VERSION 5.7 ;
  NOWIREEXTENSIONATPIN ON ;
  DIVIDERCHAR "/" ;
  BUSBITCHARS "[]" ;
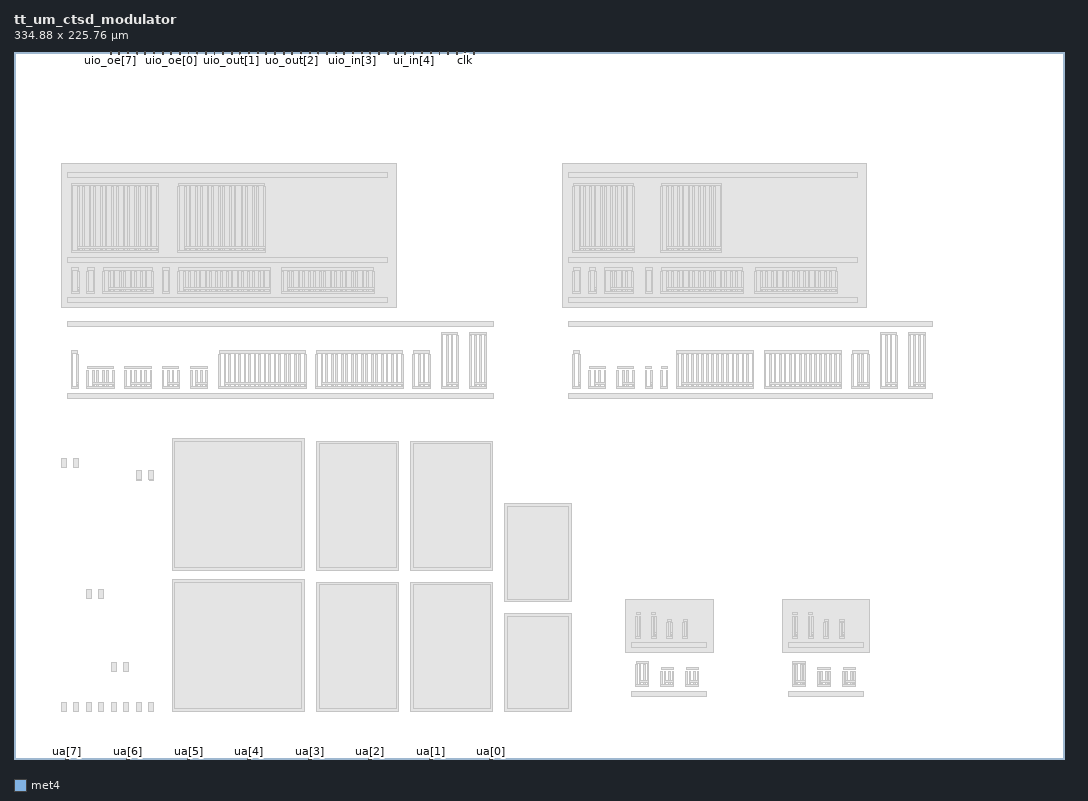
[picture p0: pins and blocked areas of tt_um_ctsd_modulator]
MACRO tt_um_ctsd_modulator
  CLASS BLOCK ;
  FOREIGN tt_um_ctsd_modulator ;
  ORIGIN 0.000 0.000 ;
  SIZE 334.880 BY 225.760 ;
  PIN clk
    DIRECTION INPUT ;
    USE SIGNAL ;
    PORT
      LAYER met4 ;
        RECT 143.830 224.760 144.130 225.760 ;
    END
  END clk
  PIN ena
    DIRECTION INPUT ;
    USE SIGNAL ;
    PORT
      LAYER met4 ;
        RECT 146.590 224.760 146.890 225.760 ;
    END
  END ena
  PIN rst_n
    DIRECTION INPUT ;
    USE SIGNAL ;
    PORT
      LAYER met4 ;
        RECT 141.070 224.760 141.370 225.760 ;
    END
  END rst_n
  PIN ua[0]
    DIRECTION INOUT ;
    USE SIGNAL ;
    PORT
      LAYER met4 ;
        RECT 151.810 0.000 152.710 1.000 ;
    END
  END ua[0]
  PIN ua[1]
    DIRECTION INOUT ;
    USE SIGNAL ;
    PORT
      LAYER met4 ;
        RECT 132.490 0.000 133.390 1.000 ;
    END
  END ua[1]
  PIN ua[2]
    DIRECTION INOUT ;
    USE SIGNAL ;
    PORT
      LAYER met4 ;
        RECT 113.170 0.000 114.070 1.000 ;
    END
  END ua[2]
  PIN ua[3]
    DIRECTION INOUT ;
    USE SIGNAL ;
    PORT
      LAYER met4 ;
        RECT 93.850 0.000 94.750 1.000 ;
    END
  END ua[3]
  PIN ua[4]
    DIRECTION INOUT ;
    USE SIGNAL ;
    PORT
      LAYER met4 ;
        RECT 74.530 0.000 75.430 1.000 ;
    END
  END ua[4]
  PIN ua[5]
    DIRECTION INOUT ;
    USE SIGNAL ;
    PORT
      LAYER met4 ;
        RECT 55.210 0.000 56.110 1.000 ;
    END
  END ua[5]
  PIN ua[6]
    DIRECTION INOUT ;
    USE SIGNAL ;
    PORT
      LAYER met4 ;
        RECT 35.890 0.000 36.790 1.000 ;
    END
  END ua[6]
  PIN ua[7]
    DIRECTION INOUT ;
    USE SIGNAL ;
    PORT
      LAYER met4 ;
        RECT 16.570 0.000 17.470 1.000 ;
    END
  END ua[7]
  PIN ui_in[0]
    DIRECTION INPUT ;
    USE SIGNAL ;
    PORT
      LAYER met4 ;
        RECT 138.310 224.760 138.610 225.760 ;
    END
  END ui_in[0]
  PIN ui_in[1]
    DIRECTION INPUT ;
    USE SIGNAL ;
    PORT
      LAYER met4 ;
        RECT 135.550 224.760 135.850 225.760 ;
    END
  END ui_in[1]
  PIN ui_in[2]
    DIRECTION INPUT ;
    USE SIGNAL ;
    PORT
      LAYER met4 ;
        RECT 132.790 224.760 133.090 225.760 ;
    END
  END ui_in[2]
  PIN ui_in[3]
    DIRECTION INPUT ;
    USE SIGNAL ;
    PORT
      LAYER met4 ;
        RECT 130.030 224.760 130.330 225.760 ;
    END
  END ui_in[3]
  PIN ui_in[4]
    DIRECTION INPUT ;
    USE SIGNAL ;
    PORT
      LAYER met4 ;
        RECT 127.270 224.760 127.570 225.760 ;
    END
  END ui_in[4]
  PIN ui_in[5]
    DIRECTION INPUT ;
    USE SIGNAL ;
    PORT
      LAYER met4 ;
        RECT 124.510 224.760 124.810 225.760 ;
    END
  END ui_in[5]
  PIN ui_in[6]
    DIRECTION INPUT ;
    USE SIGNAL ;
    PORT
      LAYER met4 ;
        RECT 121.750 224.760 122.050 225.760 ;
    END
  END ui_in[6]
  PIN ui_in[7]
    DIRECTION INPUT ;
    USE SIGNAL ;
    PORT
      LAYER met4 ;
        RECT 118.990 224.760 119.290 225.760 ;
    END
  END ui_in[7]
  PIN uio_in[0]
    DIRECTION INPUT ;
    USE SIGNAL ;
    PORT
      LAYER met4 ;
        RECT 116.230 224.760 116.530 225.760 ;
    END
  END uio_in[0]
  PIN uio_in[1]
    DIRECTION INPUT ;
    USE SIGNAL ;
    PORT
      LAYER met4 ;
        RECT 113.470 224.760 113.770 225.760 ;
    END
  END uio_in[1]
  PIN uio_in[2]
    DIRECTION INPUT ;
    USE SIGNAL ;
    PORT
      LAYER met4 ;
        RECT 110.710 224.760 111.010 225.760 ;
    END
  END uio_in[2]
  PIN uio_in[3]
    DIRECTION INPUT ;
    USE SIGNAL ;
    PORT
      LAYER met4 ;
        RECT 107.950 224.760 108.250 225.760 ;
    END
  END uio_in[3]
  PIN uio_in[4]
    DIRECTION INPUT ;
    USE SIGNAL ;
    PORT
      LAYER met4 ;
        RECT 105.190 224.760 105.490 225.760 ;
    END
  END uio_in[4]
  PIN uio_in[5]
    DIRECTION INPUT ;
    USE SIGNAL ;
    PORT
      LAYER met4 ;
        RECT 102.430 224.760 102.730 225.760 ;
    END
  END uio_in[5]
  PIN uio_in[6]
    DIRECTION INPUT ;
    USE SIGNAL ;
    PORT
      LAYER met4 ;
        RECT 99.670 224.760 99.970 225.760 ;
    END
  END uio_in[6]
  PIN uio_in[7]
    DIRECTION INPUT ;
    USE SIGNAL ;
    PORT
      LAYER met4 ;
        RECT 96.910 224.760 97.210 225.760 ;
    END
  END uio_in[7]
  PIN uio_oe[0]
    DIRECTION OUTPUT ;
    USE SIGNAL ;
    PORT
      LAYER met4 ;
        RECT 49.990 224.760 50.290 225.760 ;
    END
  END uio_oe[0]
  PIN uio_oe[1]
    DIRECTION OUTPUT ;
    USE SIGNAL ;
    PORT
      LAYER met4 ;
        RECT 47.230 224.760 47.530 225.760 ;
    END
  END uio_oe[1]
  PIN uio_oe[2]
    DIRECTION OUTPUT ;
    USE SIGNAL ;
    PORT
      LAYER met4 ;
        RECT 44.470 224.760 44.770 225.760 ;
    END
  END uio_oe[2]
  PIN uio_oe[3]
    DIRECTION OUTPUT ;
    USE SIGNAL ;
    PORT
      LAYER met4 ;
        RECT 41.710 224.760 42.010 225.760 ;
    END
  END uio_oe[3]
  PIN uio_oe[4]
    DIRECTION OUTPUT ;
    USE SIGNAL ;
    PORT
      LAYER met4 ;
        RECT 38.950 224.760 39.250 225.760 ;
    END
  END uio_oe[4]
  PIN uio_oe[5]
    DIRECTION OUTPUT ;
    USE SIGNAL ;
    PORT
      LAYER met4 ;
        RECT 36.190 224.760 36.490 225.760 ;
    END
  END uio_oe[5]
  PIN uio_oe[6]
    DIRECTION OUTPUT ;
    USE SIGNAL ;
    PORT
      LAYER met4 ;
        RECT 33.430 224.760 33.730 225.760 ;
    END
  END uio_oe[6]
  PIN uio_oe[7]
    DIRECTION OUTPUT ;
    USE SIGNAL ;
    PORT
      LAYER met4 ;
        RECT 30.670 224.760 30.970 225.760 ;
    END
  END uio_oe[7]
  PIN uio_out[0]
    DIRECTION OUTPUT ;
    USE SIGNAL ;
    PORT
      LAYER met4 ;
        RECT 72.070 224.760 72.370 225.760 ;
    END
  END uio_out[0]
  PIN uio_out[1]
    DIRECTION OUTPUT ;
    USE SIGNAL ;
    PORT
      LAYER met4 ;
        RECT 69.310 224.760 69.610 225.760 ;
    END
  END uio_out[1]
  PIN uio_out[2]
    DIRECTION OUTPUT ;
    USE SIGNAL ;
    PORT
      LAYER met4 ;
        RECT 66.550 224.760 66.850 225.760 ;
    END
  END uio_out[2]
  PIN uio_out[3]
    DIRECTION OUTPUT ;
    USE SIGNAL ;
    PORT
      LAYER met4 ;
        RECT 63.790 224.760 64.090 225.760 ;
    END
  END uio_out[3]
  PIN uio_out[4]
    DIRECTION OUTPUT ;
    USE SIGNAL ;
    PORT
      LAYER met4 ;
        RECT 61.030 224.760 61.330 225.760 ;
    END
  END uio_out[4]
  PIN uio_out[5]
    DIRECTION OUTPUT ;
    USE SIGNAL ;
    PORT
      LAYER met4 ;
        RECT 58.270 224.760 58.570 225.760 ;
    END
  END uio_out[5]
  PIN uio_out[6]
    DIRECTION OUTPUT ;
    USE SIGNAL ;
    PORT
      LAYER met4 ;
        RECT 55.510 224.760 55.810 225.760 ;
    END
  END uio_out[6]
  PIN uio_out[7]
    DIRECTION OUTPUT ;
    USE SIGNAL ;
    PORT
      LAYER met4 ;
        RECT 52.750 224.760 53.050 225.760 ;
    END
  END uio_out[7]
  PIN uo_out[0]
    DIRECTION OUTPUT ;
    USE SIGNAL ;
    PORT
      LAYER met4 ;
        RECT 94.150 224.760 94.450 225.760 ;
    END
  END uo_out[0]
  PIN uo_out[1]
    DIRECTION OUTPUT ;
    USE SIGNAL ;
    PORT
      LAYER met4 ;
        RECT 91.390 224.760 91.690 225.760 ;
    END
  END uo_out[1]
  PIN uo_out[2]
    DIRECTION OUTPUT ;
    USE SIGNAL ;
    PORT
      LAYER met4 ;
        RECT 88.630 224.760 88.930 225.760 ;
    END
  END uo_out[2]
  PIN uo_out[3]
    DIRECTION OUTPUT ;
    USE SIGNAL ;
    PORT
      LAYER met4 ;
        RECT 85.870 224.760 86.170 225.760 ;
    END
  END uo_out[3]
  PIN uo_out[4]
    DIRECTION OUTPUT ;
    USE SIGNAL ;
    PORT
      LAYER met4 ;
        RECT 83.110 224.760 83.410 225.760 ;
    END
  END uo_out[4]
  PIN uo_out[5]
    DIRECTION OUTPUT ;
    USE SIGNAL ;
    PORT
      LAYER met4 ;
        RECT 80.350 224.760 80.650 225.760 ;
    END
  END uo_out[5]
  PIN uo_out[6]
    DIRECTION OUTPUT ;
    USE SIGNAL ;
    PORT
      LAYER met4 ;
        RECT 77.590 224.760 77.890 225.760 ;
    END
  END uo_out[6]
  PIN uo_out[7]
    DIRECTION OUTPUT ;
    USE SIGNAL ;
    PORT
      LAYER met4 ;
        RECT 74.830 224.760 75.130 225.760 ;
    END
  END uo_out[7]
  OBS
      LAYER nwell ;
        RECT 15.000 144.000 122.000 190.000 ;
        RECT 175.000 144.000 272.000 190.000 ;
        RECT 195.000 34.000 223.000 51.000 ;
        RECT 245.000 34.000 273.000 51.000 ;
      LAYER li1 ;
        RECT 17.000 185.500 119.000 187.100 ;
        RECT 177.000 185.500 269.000 187.100 ;
        RECT 18.400 182.950 46.000 183.650 ;
        RECT 52.400 182.950 80.000 183.650 ;
        RECT 178.400 182.950 197.600 183.650 ;
        RECT 206.400 182.950 225.600 183.650 ;
        RECT 18.250 162.150 18.800 182.500 ;
        RECT 20.400 162.500 20.950 182.500 ;
        RECT 21.850 162.150 22.400 182.500 ;
        RECT 24.000 162.500 24.550 182.500 ;
        RECT 25.450 162.150 26.000 182.500 ;
        RECT 27.600 162.500 28.150 182.500 ;
        RECT 29.050 162.150 29.600 182.500 ;
        RECT 31.200 162.500 31.750 182.500 ;
        RECT 32.650 162.150 33.200 182.500 ;
        RECT 34.800 162.500 35.350 182.500 ;
        RECT 36.250 162.150 36.800 182.500 ;
        RECT 38.400 162.500 38.950 182.500 ;
        RECT 39.850 162.150 40.400 182.500 ;
        RECT 42.000 162.500 42.550 182.500 ;
        RECT 43.450 162.150 44.000 182.500 ;
        RECT 45.600 162.500 46.150 182.500 ;
        RECT 52.250 162.150 52.800 182.500 ;
        RECT 54.400 162.500 54.950 182.500 ;
        RECT 55.850 162.150 56.400 182.500 ;
        RECT 58.000 162.500 58.550 182.500 ;
        RECT 59.450 162.150 60.000 182.500 ;
        RECT 61.600 162.500 62.150 182.500 ;
        RECT 63.050 162.150 63.600 182.500 ;
        RECT 65.200 162.500 65.750 182.500 ;
        RECT 66.650 162.150 67.200 182.500 ;
        RECT 68.800 162.500 69.350 182.500 ;
        RECT 70.250 162.150 70.800 182.500 ;
        RECT 72.400 162.500 72.950 182.500 ;
        RECT 73.850 162.150 74.400 182.500 ;
        RECT 76.000 162.500 76.550 182.500 ;
        RECT 77.450 162.150 78.000 182.500 ;
        RECT 79.600 162.500 80.150 182.500 ;
        RECT 178.250 162.150 178.800 182.500 ;
        RECT 180.200 162.500 180.750 182.500 ;
        RECT 181.650 162.150 182.200 182.500 ;
        RECT 183.600 162.500 184.150 182.500 ;
        RECT 185.050 162.150 185.600 182.500 ;
        RECT 187.000 162.500 187.550 182.500 ;
        RECT 188.450 162.150 189.000 182.500 ;
        RECT 190.400 162.500 190.950 182.500 ;
        RECT 191.850 162.150 192.400 182.500 ;
        RECT 193.800 162.500 194.350 182.500 ;
        RECT 195.250 162.150 195.800 182.500 ;
        RECT 197.200 162.500 197.750 182.500 ;
        RECT 206.250 162.150 206.800 182.500 ;
        RECT 208.200 162.500 208.750 182.500 ;
        RECT 209.650 162.150 210.200 182.500 ;
        RECT 211.600 162.500 212.150 182.500 ;
        RECT 213.050 162.150 213.600 182.500 ;
        RECT 215.000 162.500 215.550 182.500 ;
        RECT 216.450 162.150 217.000 182.500 ;
        RECT 218.400 162.500 218.950 182.500 ;
        RECT 219.850 162.150 220.400 182.500 ;
        RECT 221.800 162.500 222.350 182.500 ;
        RECT 223.250 162.150 223.800 182.500 ;
        RECT 225.200 162.500 225.750 182.500 ;
        RECT 18.250 161.550 46.150 162.150 ;
        RECT 52.250 161.550 80.150 162.150 ;
        RECT 178.250 161.550 197.750 162.150 ;
        RECT 206.250 161.550 225.750 162.150 ;
        RECT 17.000 158.500 119.000 160.100 ;
        RECT 177.000 158.500 269.000 160.100 ;
        RECT 18.400 155.950 20.600 156.650 ;
        RECT 23.400 155.950 25.600 156.650 ;
        RECT 28.400 155.950 44.200 156.650 ;
        RECT 47.400 155.950 49.600 156.650 ;
        RECT 52.400 155.950 81.800 156.650 ;
        RECT 85.400 155.950 114.800 156.650 ;
        RECT 178.400 155.950 180.600 156.650 ;
        RECT 183.400 155.950 185.600 156.650 ;
        RECT 188.400 155.950 197.400 156.650 ;
        RECT 201.400 155.950 203.600 156.650 ;
        RECT 206.400 155.950 232.400 156.650 ;
        RECT 236.400 155.950 262.400 156.650 ;
        RECT 18.250 149.150 18.800 155.500 ;
        RECT 20.200 149.500 20.750 155.500 ;
        RECT 23.250 149.150 23.800 155.500 ;
        RECT 25.200 149.500 25.750 155.500 ;
        RECT 28.250 149.150 28.800 155.500 ;
        RECT 30.200 149.500 30.750 155.500 ;
        RECT 31.650 149.150 32.200 155.500 ;
        RECT 33.600 149.500 34.150 155.500 ;
        RECT 35.050 149.150 35.600 155.500 ;
        RECT 37.000 149.500 37.550 155.500 ;
        RECT 38.450 149.150 39.000 155.500 ;
        RECT 40.400 149.500 40.950 155.500 ;
        RECT 41.850 149.150 42.400 155.500 ;
        RECT 43.800 149.500 44.350 155.500 ;
        RECT 47.250 149.150 47.800 155.500 ;
        RECT 49.200 149.500 49.750 155.500 ;
        RECT 52.250 149.150 52.800 155.500 ;
        RECT 54.200 149.500 54.750 155.500 ;
        RECT 55.650 149.150 56.200 155.500 ;
        RECT 57.600 149.500 58.150 155.500 ;
        RECT 59.050 149.150 59.600 155.500 ;
        RECT 61.000 149.500 61.550 155.500 ;
        RECT 62.450 149.150 63.000 155.500 ;
        RECT 64.400 149.500 64.950 155.500 ;
        RECT 65.850 149.150 66.400 155.500 ;
        RECT 67.800 149.500 68.350 155.500 ;
        RECT 69.250 149.150 69.800 155.500 ;
        RECT 71.200 149.500 71.750 155.500 ;
        RECT 72.650 149.150 73.200 155.500 ;
        RECT 74.600 149.500 75.150 155.500 ;
        RECT 76.050 149.150 76.600 155.500 ;
        RECT 78.000 149.500 78.550 155.500 ;
        RECT 79.450 149.150 80.000 155.500 ;
        RECT 81.400 149.500 81.950 155.500 ;
        RECT 85.250 149.150 85.800 155.500 ;
        RECT 87.200 149.500 87.750 155.500 ;
        RECT 88.650 149.150 89.200 155.500 ;
        RECT 90.600 149.500 91.150 155.500 ;
        RECT 92.050 149.150 92.600 155.500 ;
        RECT 94.000 149.500 94.550 155.500 ;
        RECT 95.450 149.150 96.000 155.500 ;
        RECT 97.400 149.500 97.950 155.500 ;
        RECT 98.850 149.150 99.400 155.500 ;
        RECT 100.800 149.500 101.350 155.500 ;
        RECT 102.250 149.150 102.800 155.500 ;
        RECT 104.200 149.500 104.750 155.500 ;
        RECT 105.650 149.150 106.200 155.500 ;
        RECT 107.600 149.500 108.150 155.500 ;
        RECT 109.050 149.150 109.600 155.500 ;
        RECT 111.000 149.500 111.550 155.500 ;
        RECT 112.450 149.150 113.000 155.500 ;
        RECT 114.400 149.500 114.950 155.500 ;
        RECT 178.250 149.150 178.800 155.500 ;
        RECT 180.200 149.500 180.750 155.500 ;
        RECT 183.250 149.150 183.800 155.500 ;
        RECT 185.200 149.500 185.750 155.500 ;
        RECT 188.250 149.150 188.800 155.500 ;
        RECT 190.200 149.500 190.750 155.500 ;
        RECT 191.650 149.150 192.200 155.500 ;
        RECT 193.600 149.500 194.150 155.500 ;
        RECT 195.050 149.150 195.600 155.500 ;
        RECT 197.000 149.500 197.550 155.500 ;
        RECT 201.250 149.150 201.800 155.500 ;
        RECT 203.200 149.500 203.750 155.500 ;
        RECT 206.250 149.150 206.800 155.500 ;
        RECT 208.200 149.500 208.750 155.500 ;
        RECT 209.650 149.150 210.200 155.500 ;
        RECT 211.600 149.500 212.150 155.500 ;
        RECT 213.050 149.150 213.600 155.500 ;
        RECT 215.000 149.500 215.550 155.500 ;
        RECT 216.450 149.150 217.000 155.500 ;
        RECT 218.400 149.500 218.950 155.500 ;
        RECT 219.850 149.150 220.400 155.500 ;
        RECT 221.800 149.500 222.350 155.500 ;
        RECT 223.250 149.150 223.800 155.500 ;
        RECT 225.200 149.500 225.750 155.500 ;
        RECT 226.650 149.150 227.200 155.500 ;
        RECT 228.600 149.500 229.150 155.500 ;
        RECT 230.050 149.150 230.600 155.500 ;
        RECT 232.000 149.500 232.550 155.500 ;
        RECT 236.250 149.150 236.800 155.500 ;
        RECT 238.200 149.500 238.750 155.500 ;
        RECT 239.650 149.150 240.200 155.500 ;
        RECT 241.600 149.500 242.150 155.500 ;
        RECT 243.050 149.150 243.600 155.500 ;
        RECT 245.000 149.500 245.550 155.500 ;
        RECT 246.450 149.150 247.000 155.500 ;
        RECT 248.400 149.500 248.950 155.500 ;
        RECT 249.850 149.150 250.400 155.500 ;
        RECT 251.800 149.500 252.350 155.500 ;
        RECT 253.250 149.150 253.800 155.500 ;
        RECT 255.200 149.500 255.750 155.500 ;
        RECT 256.650 149.150 257.200 155.500 ;
        RECT 258.600 149.500 259.150 155.500 ;
        RECT 260.050 149.150 260.600 155.500 ;
        RECT 262.000 149.500 262.550 155.500 ;
        RECT 18.250 148.550 20.750 149.150 ;
        RECT 23.250 148.550 25.750 149.150 ;
        RECT 28.250 148.550 44.350 149.150 ;
        RECT 47.250 148.550 49.750 149.150 ;
        RECT 52.250 148.550 81.950 149.150 ;
        RECT 85.250 148.550 114.950 149.150 ;
        RECT 178.250 148.550 180.750 149.150 ;
        RECT 183.250 148.550 185.750 149.150 ;
        RECT 188.250 148.550 197.550 149.150 ;
        RECT 201.250 148.550 203.750 149.150 ;
        RECT 206.250 148.550 232.550 149.150 ;
        RECT 236.250 148.550 262.550 149.150 ;
        RECT 17.000 145.500 119.000 147.100 ;
        RECT 177.000 145.500 269.000 147.100 ;
        RECT 17.000 138.000 153.000 139.600 ;
        RECT 177.000 138.000 293.000 139.600 ;
        RECT 136.400 135.450 141.600 136.150 ;
        RECT 145.400 135.450 150.600 136.150 ;
        RECT 276.400 135.450 281.600 136.150 ;
        RECT 285.400 135.450 290.600 136.150 ;
        RECT 18.400 129.450 20.400 130.150 ;
        RECT 65.400 129.450 93.000 130.150 ;
        RECT 96.400 129.450 124.000 130.150 ;
        RECT 127.400 129.450 132.600 130.150 ;
        RECT 18.250 118.650 18.800 129.000 ;
        RECT 20.000 119.000 20.550 129.000 ;
        RECT 23.400 124.450 31.800 125.150 ;
        RECT 35.400 124.450 43.800 125.150 ;
        RECT 47.400 124.450 52.600 125.150 ;
        RECT 56.400 124.450 61.600 125.150 ;
        RECT 23.250 118.650 23.800 124.000 ;
        RECT 25.000 119.000 25.550 124.000 ;
        RECT 26.450 118.650 27.000 124.000 ;
        RECT 28.200 119.000 28.750 124.000 ;
        RECT 29.650 118.650 30.200 124.000 ;
        RECT 31.400 119.000 31.950 124.000 ;
        RECT 35.250 118.650 35.800 124.000 ;
        RECT 37.000 119.000 37.550 124.000 ;
        RECT 38.450 118.650 39.000 124.000 ;
        RECT 40.200 119.000 40.750 124.000 ;
        RECT 41.650 118.650 42.200 124.000 ;
        RECT 43.400 119.000 43.950 124.000 ;
        RECT 47.250 118.650 47.800 124.000 ;
        RECT 49.000 119.000 49.550 124.000 ;
        RECT 50.450 118.650 51.000 124.000 ;
        RECT 52.200 119.000 52.750 124.000 ;
        RECT 56.250 118.650 56.800 124.000 ;
        RECT 58.000 119.000 58.550 124.000 ;
        RECT 59.450 118.650 60.000 124.000 ;
        RECT 61.200 119.000 61.750 124.000 ;
        RECT 65.250 118.650 65.800 129.000 ;
        RECT 67.000 119.000 67.550 129.000 ;
        RECT 68.450 118.650 69.000 129.000 ;
        RECT 70.200 119.000 70.750 129.000 ;
        RECT 71.650 118.650 72.200 129.000 ;
        RECT 73.400 119.000 73.950 129.000 ;
        RECT 74.850 118.650 75.400 129.000 ;
        RECT 76.600 119.000 77.150 129.000 ;
        RECT 78.050 118.650 78.600 129.000 ;
        RECT 79.800 119.000 80.350 129.000 ;
        RECT 81.250 118.650 81.800 129.000 ;
        RECT 83.000 119.000 83.550 129.000 ;
        RECT 84.450 118.650 85.000 129.000 ;
        RECT 86.200 119.000 86.750 129.000 ;
        RECT 87.650 118.650 88.200 129.000 ;
        RECT 89.400 119.000 89.950 129.000 ;
        RECT 90.850 118.650 91.400 129.000 ;
        RECT 92.600 119.000 93.150 129.000 ;
        RECT 96.250 118.650 96.800 129.000 ;
        RECT 98.000 119.000 98.550 129.000 ;
        RECT 99.450 118.650 100.000 129.000 ;
        RECT 101.200 119.000 101.750 129.000 ;
        RECT 102.650 118.650 103.200 129.000 ;
        RECT 104.400 119.000 104.950 129.000 ;
        RECT 105.850 118.650 106.400 129.000 ;
        RECT 107.600 119.000 108.150 129.000 ;
        RECT 109.050 118.650 109.600 129.000 ;
        RECT 110.800 119.000 111.350 129.000 ;
        RECT 112.250 118.650 112.800 129.000 ;
        RECT 114.000 119.000 114.550 129.000 ;
        RECT 115.450 118.650 116.000 129.000 ;
        RECT 117.200 119.000 117.750 129.000 ;
        RECT 118.650 118.650 119.200 129.000 ;
        RECT 120.400 119.000 120.950 129.000 ;
        RECT 121.850 118.650 122.400 129.000 ;
        RECT 123.600 119.000 124.150 129.000 ;
        RECT 127.250 118.650 127.800 129.000 ;
        RECT 129.000 119.000 129.550 129.000 ;
        RECT 130.450 118.650 131.000 129.000 ;
        RECT 132.200 119.000 132.750 129.000 ;
        RECT 136.250 118.650 136.800 135.000 ;
        RECT 138.000 119.000 138.550 135.000 ;
        RECT 139.450 118.650 140.000 135.000 ;
        RECT 141.200 119.000 141.750 135.000 ;
        RECT 145.250 118.650 145.800 135.000 ;
        RECT 147.000 119.000 147.550 135.000 ;
        RECT 148.450 118.650 149.000 135.000 ;
        RECT 150.200 119.000 150.750 135.000 ;
        RECT 178.400 129.450 180.400 130.150 ;
        RECT 211.400 129.450 235.800 130.150 ;
        RECT 239.400 129.450 263.800 130.150 ;
        RECT 267.400 129.450 272.600 130.150 ;
        RECT 178.250 118.650 178.800 129.000 ;
        RECT 180.000 119.000 180.550 129.000 ;
        RECT 183.400 124.450 188.600 125.150 ;
        RECT 192.400 124.450 197.600 125.150 ;
        RECT 201.400 124.450 203.400 125.150 ;
        RECT 206.400 124.450 208.400 125.150 ;
        RECT 183.250 118.650 183.800 124.000 ;
        RECT 185.000 119.000 185.550 124.000 ;
        RECT 186.450 118.650 187.000 124.000 ;
        RECT 188.200 119.000 188.750 124.000 ;
        RECT 192.250 118.650 192.800 124.000 ;
        RECT 194.000 119.000 194.550 124.000 ;
        RECT 195.450 118.650 196.000 124.000 ;
        RECT 197.200 119.000 197.750 124.000 ;
        RECT 201.250 118.650 201.800 124.000 ;
        RECT 203.000 119.000 203.550 124.000 ;
        RECT 206.250 118.650 206.800 124.000 ;
        RECT 208.000 119.000 208.550 124.000 ;
        RECT 211.250 118.650 211.800 129.000 ;
        RECT 213.000 119.000 213.550 129.000 ;
        RECT 214.450 118.650 215.000 129.000 ;
        RECT 216.200 119.000 216.750 129.000 ;
        RECT 217.650 118.650 218.200 129.000 ;
        RECT 219.400 119.000 219.950 129.000 ;
        RECT 220.850 118.650 221.400 129.000 ;
        RECT 222.600 119.000 223.150 129.000 ;
        RECT 224.050 118.650 224.600 129.000 ;
        RECT 225.800 119.000 226.350 129.000 ;
        RECT 227.250 118.650 227.800 129.000 ;
        RECT 229.000 119.000 229.550 129.000 ;
        RECT 230.450 118.650 231.000 129.000 ;
        RECT 232.200 119.000 232.750 129.000 ;
        RECT 233.650 118.650 234.200 129.000 ;
        RECT 235.400 119.000 235.950 129.000 ;
        RECT 239.250 118.650 239.800 129.000 ;
        RECT 241.000 119.000 241.550 129.000 ;
        RECT 242.450 118.650 243.000 129.000 ;
        RECT 244.200 119.000 244.750 129.000 ;
        RECT 245.650 118.650 246.200 129.000 ;
        RECT 247.400 119.000 247.950 129.000 ;
        RECT 248.850 118.650 249.400 129.000 ;
        RECT 250.600 119.000 251.150 129.000 ;
        RECT 252.050 118.650 252.600 129.000 ;
        RECT 253.800 119.000 254.350 129.000 ;
        RECT 255.250 118.650 255.800 129.000 ;
        RECT 257.000 119.000 257.550 129.000 ;
        RECT 258.450 118.650 259.000 129.000 ;
        RECT 260.200 119.000 260.750 129.000 ;
        RECT 261.650 118.650 262.200 129.000 ;
        RECT 263.400 119.000 263.950 129.000 ;
        RECT 267.250 118.650 267.800 129.000 ;
        RECT 269.000 119.000 269.550 129.000 ;
        RECT 270.450 118.650 271.000 129.000 ;
        RECT 272.200 119.000 272.750 129.000 ;
        RECT 276.250 118.650 276.800 135.000 ;
        RECT 278.000 119.000 278.550 135.000 ;
        RECT 279.450 118.650 280.000 135.000 ;
        RECT 281.200 119.000 281.750 135.000 ;
        RECT 285.250 118.650 285.800 135.000 ;
        RECT 287.000 119.000 287.550 135.000 ;
        RECT 288.450 118.650 289.000 135.000 ;
        RECT 290.200 119.000 290.750 135.000 ;
        RECT 18.250 118.050 20.550 118.650 ;
        RECT 23.250 118.050 31.950 118.650 ;
        RECT 35.250 118.050 43.950 118.650 ;
        RECT 47.250 118.050 52.750 118.650 ;
        RECT 56.250 118.050 61.750 118.650 ;
        RECT 65.250 118.050 93.150 118.650 ;
        RECT 96.250 118.050 124.150 118.650 ;
        RECT 127.250 118.050 132.750 118.650 ;
        RECT 136.250 118.050 141.750 118.650 ;
        RECT 145.250 118.050 150.750 118.650 ;
        RECT 178.250 118.050 180.550 118.650 ;
        RECT 183.250 118.050 188.750 118.650 ;
        RECT 192.250 118.050 197.750 118.650 ;
        RECT 201.250 118.050 203.550 118.650 ;
        RECT 206.250 118.050 208.550 118.650 ;
        RECT 211.250 118.050 235.950 118.650 ;
        RECT 239.250 118.050 263.950 118.650 ;
        RECT 267.250 118.050 272.750 118.650 ;
        RECT 276.250 118.050 281.750 118.650 ;
        RECT 285.250 118.050 290.750 118.650 ;
        RECT 17.000 115.000 153.000 116.600 ;
        RECT 177.000 115.000 293.000 116.600 ;
        RECT 15.000 92.940 16.610 95.840 ;
        RECT 19.000 92.940 20.610 95.840 ;
        RECT 15.100 92.840 16.510 92.940 ;
        RECT 19.100 92.840 20.510 92.940 ;
        RECT 39.000 89.040 40.610 91.940 ;
        RECT 43.000 89.040 44.610 91.940 ;
        RECT 39.100 88.940 40.510 89.040 ;
        RECT 43.100 88.940 44.510 89.040 ;
        RECT 23.000 51.290 24.610 54.190 ;
        RECT 27.000 51.290 28.610 54.190 ;
        RECT 23.100 51.190 24.510 51.290 ;
        RECT 27.100 51.190 28.510 51.290 ;
        RECT 198.400 45.950 199.750 46.650 ;
        RECT 203.400 45.950 204.750 46.650 ;
        RECT 248.400 45.950 249.750 46.650 ;
        RECT 253.400 45.950 254.750 46.650 ;
        RECT 198.250 39.150 198.800 45.500 ;
        RECT 199.350 39.500 199.900 45.500 ;
        RECT 203.250 39.150 203.800 45.500 ;
        RECT 204.350 39.500 204.900 45.500 ;
        RECT 208.400 43.950 209.750 44.650 ;
        RECT 213.400 43.950 214.750 44.650 ;
        RECT 208.250 39.150 208.800 43.500 ;
        RECT 209.350 39.500 209.900 43.500 ;
        RECT 213.250 39.150 213.800 43.500 ;
        RECT 214.350 39.500 214.900 43.500 ;
        RECT 248.250 39.150 248.800 45.500 ;
        RECT 249.350 39.500 249.900 45.500 ;
        RECT 253.250 39.150 253.800 45.500 ;
        RECT 254.350 39.500 254.900 45.500 ;
        RECT 258.400 43.950 259.750 44.650 ;
        RECT 263.400 43.950 264.750 44.650 ;
        RECT 258.250 39.150 258.800 43.500 ;
        RECT 259.350 39.500 259.900 43.500 ;
        RECT 263.250 39.150 263.800 43.500 ;
        RECT 264.350 39.500 264.900 43.500 ;
        RECT 198.250 38.550 199.900 39.150 ;
        RECT 203.250 38.550 204.900 39.150 ;
        RECT 208.250 38.550 209.900 39.150 ;
        RECT 213.250 38.550 214.900 39.150 ;
        RECT 248.250 38.550 249.900 39.150 ;
        RECT 253.250 38.550 254.900 39.150 ;
        RECT 258.250 38.550 259.900 39.150 ;
        RECT 263.250 38.550 264.900 39.150 ;
        RECT 197.000 35.500 221.000 37.100 ;
        RECT 247.000 35.500 271.000 37.100 ;
        RECT 31.000 27.940 32.610 30.840 ;
        RECT 35.000 27.940 36.610 30.840 ;
        RECT 198.400 30.450 202.300 31.150 ;
        RECT 248.400 30.450 252.300 31.150 ;
        RECT 31.100 27.840 32.510 27.940 ;
        RECT 35.100 27.840 36.510 27.940 ;
        RECT 198.250 23.650 198.800 30.000 ;
        RECT 199.350 24.000 199.900 30.000 ;
        RECT 200.800 23.650 201.350 30.000 ;
        RECT 201.900 24.000 202.450 30.000 ;
        RECT 206.400 28.450 210.300 29.150 ;
        RECT 214.400 28.450 218.300 29.150 ;
        RECT 206.250 23.650 206.800 28.000 ;
        RECT 207.350 24.000 207.900 28.000 ;
        RECT 208.800 23.650 209.350 28.000 ;
        RECT 209.900 24.000 210.450 28.000 ;
        RECT 214.250 23.650 214.800 28.000 ;
        RECT 215.350 24.000 215.900 28.000 ;
        RECT 216.800 23.650 217.350 28.000 ;
        RECT 217.900 24.000 218.450 28.000 ;
        RECT 248.250 23.650 248.800 30.000 ;
        RECT 249.350 24.000 249.900 30.000 ;
        RECT 250.800 23.650 251.350 30.000 ;
        RECT 251.900 24.000 252.450 30.000 ;
        RECT 256.400 28.450 260.300 29.150 ;
        RECT 264.400 28.450 268.300 29.150 ;
        RECT 256.250 23.650 256.800 28.000 ;
        RECT 257.350 24.000 257.900 28.000 ;
        RECT 258.800 23.650 259.350 28.000 ;
        RECT 259.900 24.000 260.450 28.000 ;
        RECT 264.250 23.650 264.800 28.000 ;
        RECT 265.350 24.000 265.900 28.000 ;
        RECT 266.800 23.650 267.350 28.000 ;
        RECT 267.900 24.000 268.450 28.000 ;
        RECT 198.250 23.050 202.450 23.650 ;
        RECT 206.250 23.050 210.450 23.650 ;
        RECT 214.250 23.050 218.450 23.650 ;
        RECT 248.250 23.050 252.450 23.650 ;
        RECT 256.250 23.050 260.450 23.650 ;
        RECT 264.250 23.050 268.450 23.650 ;
        RECT 197.000 20.000 221.000 21.600 ;
        RECT 247.000 20.000 271.000 21.600 ;
        RECT 15.100 17.900 16.510 18.000 ;
        RECT 19.100 17.900 20.510 18.000 ;
        RECT 23.100 17.900 24.510 18.000 ;
        RECT 27.100 17.900 28.510 18.000 ;
        RECT 31.100 17.900 32.510 18.000 ;
        RECT 35.100 17.900 36.510 18.000 ;
        RECT 39.100 17.900 40.510 18.000 ;
        RECT 43.100 17.900 44.510 18.000 ;
        RECT 15.000 15.000 16.610 17.900 ;
        RECT 19.000 15.000 20.610 17.900 ;
        RECT 23.000 15.000 24.610 17.900 ;
        RECT 27.000 15.000 28.610 17.900 ;
        RECT 31.000 15.000 32.610 17.900 ;
        RECT 35.000 15.000 36.610 17.900 ;
        RECT 39.000 15.000 40.610 17.900 ;
        RECT 43.000 15.000 44.610 17.900 ;
      LAYER mcon ;
        RECT 17.250 185.750 118.750 186.850 ;
        RECT 177.250 185.750 268.750 186.850 ;
        RECT 45.500 183.130 45.820 183.470 ;
        RECT 79.500 183.130 79.820 183.470 ;
        RECT 197.100 183.130 197.420 183.470 ;
        RECT 225.100 183.130 225.420 183.470 ;
        RECT 18.450 161.700 18.850 162.000 ;
        RECT 52.450 161.700 52.850 162.000 ;
        RECT 178.450 161.700 178.850 162.000 ;
        RECT 206.450 161.700 206.850 162.000 ;
        RECT 17.250 158.750 118.750 159.850 ;
        RECT 177.250 158.750 268.750 159.850 ;
        RECT 20.100 156.130 20.420 156.470 ;
        RECT 25.100 156.130 25.420 156.470 ;
        RECT 43.700 156.130 44.020 156.470 ;
        RECT 49.100 156.130 49.420 156.470 ;
        RECT 81.300 156.130 81.620 156.470 ;
        RECT 114.300 156.130 114.620 156.470 ;
        RECT 180.100 156.130 180.420 156.470 ;
        RECT 185.100 156.130 185.420 156.470 ;
        RECT 196.900 156.130 197.220 156.470 ;
        RECT 203.100 156.130 203.420 156.470 ;
        RECT 231.900 156.130 232.220 156.470 ;
        RECT 261.900 156.130 262.220 156.470 ;
        RECT 18.450 148.700 18.850 149.000 ;
        RECT 23.450 148.700 23.850 149.000 ;
        RECT 28.450 148.700 28.850 149.000 ;
        RECT 47.450 148.700 47.850 149.000 ;
        RECT 52.450 148.700 52.850 149.000 ;
        RECT 85.450 148.700 85.850 149.000 ;
        RECT 178.450 148.700 178.850 149.000 ;
        RECT 183.450 148.700 183.850 149.000 ;
        RECT 188.450 148.700 188.850 149.000 ;
        RECT 201.450 148.700 201.850 149.000 ;
        RECT 206.450 148.700 206.850 149.000 ;
        RECT 236.450 148.700 236.850 149.000 ;
        RECT 17.250 145.750 118.750 146.850 ;
        RECT 177.250 145.750 268.750 146.850 ;
        RECT 17.250 138.250 152.750 139.350 ;
        RECT 177.250 138.250 292.750 139.350 ;
        RECT 141.100 135.630 141.420 135.970 ;
        RECT 150.100 135.630 150.420 135.970 ;
        RECT 281.100 135.630 281.420 135.970 ;
        RECT 290.100 135.630 290.420 135.970 ;
        RECT 19.900 129.630 20.220 129.970 ;
        RECT 92.500 129.630 92.820 129.970 ;
        RECT 123.500 129.630 123.820 129.970 ;
        RECT 132.100 129.630 132.420 129.970 ;
        RECT 31.300 124.630 31.620 124.970 ;
        RECT 43.300 124.630 43.620 124.970 ;
        RECT 52.100 124.630 52.420 124.970 ;
        RECT 61.100 124.630 61.420 124.970 ;
        RECT 179.900 129.630 180.220 129.970 ;
        RECT 235.300 129.630 235.620 129.970 ;
        RECT 263.300 129.630 263.620 129.970 ;
        RECT 272.100 129.630 272.420 129.970 ;
        RECT 188.100 124.630 188.420 124.970 ;
        RECT 197.100 124.630 197.420 124.970 ;
        RECT 202.900 124.630 203.220 124.970 ;
        RECT 207.900 124.630 208.220 124.970 ;
        RECT 18.450 118.200 18.850 118.500 ;
        RECT 23.450 118.200 23.850 118.500 ;
        RECT 35.450 118.200 35.850 118.500 ;
        RECT 47.450 118.200 47.850 118.500 ;
        RECT 56.450 118.200 56.850 118.500 ;
        RECT 65.450 118.200 65.850 118.500 ;
        RECT 96.450 118.200 96.850 118.500 ;
        RECT 127.450 118.200 127.850 118.500 ;
        RECT 136.450 118.200 136.850 118.500 ;
        RECT 145.450 118.200 145.850 118.500 ;
        RECT 178.450 118.200 178.850 118.500 ;
        RECT 183.450 118.200 183.850 118.500 ;
        RECT 192.450 118.200 192.850 118.500 ;
        RECT 201.450 118.200 201.850 118.500 ;
        RECT 206.450 118.200 206.850 118.500 ;
        RECT 211.450 118.200 211.850 118.500 ;
        RECT 239.450 118.200 239.850 118.500 ;
        RECT 267.450 118.200 267.850 118.500 ;
        RECT 276.450 118.200 276.850 118.500 ;
        RECT 285.450 118.200 285.850 118.500 ;
        RECT 17.250 115.250 152.750 116.350 ;
        RECT 177.250 115.250 292.750 116.350 ;
        RECT 15.400 95.240 16.210 95.690 ;
        RECT 19.400 95.240 20.210 95.690 ;
        RECT 39.400 91.340 40.210 91.790 ;
        RECT 43.400 91.340 44.210 91.790 ;
        RECT 23.400 53.590 24.210 54.040 ;
        RECT 27.400 53.590 28.210 54.040 ;
        RECT 199.250 46.130 199.570 46.470 ;
        RECT 204.250 46.130 204.570 46.470 ;
        RECT 249.250 46.130 249.570 46.470 ;
        RECT 254.250 46.130 254.570 46.470 ;
        RECT 209.250 44.130 209.570 44.470 ;
        RECT 214.250 44.130 214.570 44.470 ;
        RECT 259.250 44.130 259.570 44.470 ;
        RECT 264.250 44.130 264.570 44.470 ;
        RECT 198.450 38.700 198.850 39.000 ;
        RECT 203.450 38.700 203.850 39.000 ;
        RECT 208.450 38.700 208.850 39.000 ;
        RECT 213.450 38.700 213.850 39.000 ;
        RECT 248.450 38.700 248.850 39.000 ;
        RECT 253.450 38.700 253.850 39.000 ;
        RECT 258.450 38.700 258.850 39.000 ;
        RECT 263.450 38.700 263.850 39.000 ;
        RECT 197.250 35.750 220.750 36.850 ;
        RECT 247.250 35.750 270.750 36.850 ;
        RECT 31.400 30.240 32.210 30.690 ;
        RECT 35.400 30.240 36.210 30.690 ;
        RECT 201.800 30.630 202.120 30.970 ;
        RECT 251.800 30.630 252.120 30.970 ;
        RECT 209.800 28.630 210.120 28.970 ;
        RECT 217.800 28.630 218.120 28.970 ;
        RECT 259.800 28.630 260.120 28.970 ;
        RECT 267.800 28.630 268.120 28.970 ;
        RECT 198.450 23.200 198.850 23.500 ;
        RECT 206.450 23.200 206.850 23.500 ;
        RECT 214.450 23.200 214.850 23.500 ;
        RECT 248.450 23.200 248.850 23.500 ;
        RECT 256.450 23.200 256.850 23.500 ;
        RECT 264.450 23.200 264.850 23.500 ;
        RECT 197.250 20.250 220.750 21.350 ;
        RECT 247.250 20.250 270.750 21.350 ;
        RECT 15.400 15.150 16.210 15.600 ;
        RECT 19.400 15.150 20.210 15.600 ;
        RECT 23.400 15.150 24.210 15.600 ;
        RECT 27.400 15.150 28.210 15.600 ;
        RECT 31.400 15.150 32.210 15.600 ;
        RECT 35.400 15.150 36.210 15.600 ;
        RECT 39.400 15.150 40.210 15.600 ;
        RECT 43.400 15.150 44.210 15.600 ;
      LAYER met1 ;
        RECT 17.000 185.500 119.000 187.100 ;
        RECT 177.000 185.500 269.000 187.100 ;
        RECT 18.400 182.950 46.000 183.650 ;
        RECT 52.400 182.950 80.000 183.650 ;
        RECT 178.400 182.950 197.600 183.650 ;
        RECT 206.400 182.950 225.600 183.650 ;
        RECT 18.250 161.550 46.150 162.150 ;
        RECT 52.250 161.550 80.150 162.150 ;
        RECT 178.250 161.550 197.750 162.150 ;
        RECT 206.250 161.550 225.750 162.150 ;
        RECT 17.000 158.500 119.000 160.100 ;
        RECT 177.000 158.500 269.000 160.100 ;
        RECT 18.400 155.950 20.600 156.650 ;
        RECT 23.400 155.950 25.600 156.650 ;
        RECT 28.400 155.950 44.200 156.650 ;
        RECT 47.400 155.950 49.600 156.650 ;
        RECT 52.400 155.950 81.800 156.650 ;
        RECT 85.400 155.950 114.800 156.650 ;
        RECT 178.400 155.950 180.600 156.650 ;
        RECT 183.400 155.950 185.600 156.650 ;
        RECT 188.400 155.950 197.400 156.650 ;
        RECT 201.400 155.950 203.600 156.650 ;
        RECT 206.400 155.950 232.400 156.650 ;
        RECT 236.400 155.950 262.400 156.650 ;
        RECT 18.250 148.550 20.750 149.150 ;
        RECT 23.250 148.550 25.750 149.150 ;
        RECT 28.250 148.550 44.350 149.150 ;
        RECT 47.250 148.550 49.750 149.150 ;
        RECT 52.250 148.550 81.950 149.150 ;
        RECT 85.250 148.550 114.950 149.150 ;
        RECT 178.250 148.550 180.750 149.150 ;
        RECT 183.250 148.550 185.750 149.150 ;
        RECT 188.250 148.550 197.550 149.150 ;
        RECT 201.250 148.550 203.750 149.150 ;
        RECT 206.250 148.550 232.550 149.150 ;
        RECT 236.250 148.550 262.550 149.150 ;
        RECT 17.000 145.500 119.000 147.100 ;
        RECT 177.000 145.500 269.000 147.100 ;
        RECT 17.000 138.000 153.000 139.600 ;
        RECT 177.000 138.000 293.000 139.600 ;
        RECT 136.400 135.450 141.600 136.150 ;
        RECT 145.400 135.450 150.600 136.150 ;
        RECT 276.400 135.450 281.600 136.150 ;
        RECT 285.400 135.450 290.600 136.150 ;
        RECT 18.400 129.450 20.400 130.150 ;
        RECT 65.400 129.450 93.000 130.150 ;
        RECT 96.400 129.450 124.000 130.150 ;
        RECT 127.400 129.450 132.600 130.150 ;
        RECT 178.400 129.450 180.400 130.150 ;
        RECT 211.400 129.450 235.800 130.150 ;
        RECT 239.400 129.450 263.800 130.150 ;
        RECT 267.400 129.450 272.600 130.150 ;
        RECT 23.400 124.450 31.800 125.150 ;
        RECT 35.400 124.450 43.800 125.150 ;
        RECT 47.400 124.450 52.600 125.150 ;
        RECT 56.400 124.450 61.600 125.150 ;
        RECT 183.400 124.450 188.600 125.150 ;
        RECT 192.400 124.450 197.600 125.150 ;
        RECT 201.400 124.450 203.400 125.150 ;
        RECT 206.400 124.450 208.400 125.150 ;
        RECT 18.250 118.050 20.550 118.650 ;
        RECT 23.250 118.050 31.950 118.650 ;
        RECT 35.250 118.050 43.950 118.650 ;
        RECT 47.250 118.050 52.750 118.650 ;
        RECT 56.250 118.050 61.750 118.650 ;
        RECT 65.250 118.050 93.150 118.650 ;
        RECT 96.250 118.050 124.150 118.650 ;
        RECT 127.250 118.050 132.750 118.650 ;
        RECT 136.250 118.050 141.750 118.650 ;
        RECT 145.250 118.050 150.750 118.650 ;
        RECT 178.250 118.050 180.550 118.650 ;
        RECT 183.250 118.050 188.750 118.650 ;
        RECT 192.250 118.050 197.750 118.650 ;
        RECT 201.250 118.050 203.550 118.650 ;
        RECT 206.250 118.050 208.550 118.650 ;
        RECT 211.250 118.050 235.950 118.650 ;
        RECT 239.250 118.050 263.950 118.650 ;
        RECT 267.250 118.050 272.750 118.650 ;
        RECT 276.250 118.050 281.750 118.650 ;
        RECT 285.250 118.050 290.750 118.650 ;
        RECT 17.000 115.000 153.000 116.600 ;
        RECT 177.000 115.000 293.000 116.600 ;
        RECT 15.000 92.940 16.610 95.840 ;
        RECT 19.000 92.940 20.610 95.840 ;
        RECT 39.000 89.040 40.610 91.940 ;
        RECT 43.000 89.040 44.610 91.940 ;
        RECT 23.000 51.290 24.610 54.190 ;
        RECT 27.000 51.290 28.610 54.190 ;
        RECT 198.400 45.950 199.750 46.650 ;
        RECT 203.400 45.950 204.750 46.650 ;
        RECT 248.400 45.950 249.750 46.650 ;
        RECT 253.400 45.950 254.750 46.650 ;
        RECT 208.400 43.950 209.750 44.650 ;
        RECT 213.400 43.950 214.750 44.650 ;
        RECT 258.400 43.950 259.750 44.650 ;
        RECT 263.400 43.950 264.750 44.650 ;
        RECT 198.250 38.550 199.900 39.150 ;
        RECT 203.250 38.550 204.900 39.150 ;
        RECT 208.250 38.550 209.900 39.150 ;
        RECT 213.250 38.550 214.900 39.150 ;
        RECT 248.250 38.550 249.900 39.150 ;
        RECT 253.250 38.550 254.900 39.150 ;
        RECT 258.250 38.550 259.900 39.150 ;
        RECT 263.250 38.550 264.900 39.150 ;
        RECT 197.000 35.500 221.000 37.100 ;
        RECT 247.000 35.500 271.000 37.100 ;
        RECT 31.000 27.940 32.610 30.840 ;
        RECT 35.000 27.940 36.610 30.840 ;
        RECT 198.400 30.450 202.300 31.150 ;
        RECT 248.400 30.450 252.300 31.150 ;
        RECT 206.400 28.450 210.300 29.150 ;
        RECT 214.400 28.450 218.300 29.150 ;
        RECT 256.400 28.450 260.300 29.150 ;
        RECT 264.400 28.450 268.300 29.150 ;
        RECT 198.250 23.050 202.450 23.650 ;
        RECT 206.250 23.050 210.450 23.650 ;
        RECT 214.250 23.050 218.450 23.650 ;
        RECT 248.250 23.050 252.450 23.650 ;
        RECT 256.250 23.050 260.450 23.650 ;
        RECT 264.250 23.050 268.450 23.650 ;
        RECT 197.000 20.000 221.000 21.600 ;
        RECT 247.000 20.000 271.000 21.600 ;
        RECT 15.000 15.000 16.610 17.900 ;
        RECT 19.000 15.000 20.610 17.900 ;
        RECT 23.000 15.000 24.610 17.900 ;
        RECT 27.000 15.000 28.610 17.900 ;
        RECT 31.000 15.000 32.610 17.900 ;
        RECT 35.000 15.000 36.610 17.900 ;
        RECT 39.000 15.000 40.610 17.900 ;
        RECT 43.000 15.000 44.610 17.900 ;
      LAYER met2 ;
        RECT 20.400 162.800 46.150 163.500 ;
        RECT 54.400 162.800 80.150 163.500 ;
        RECT 180.200 162.800 197.750 163.500 ;
        RECT 208.200 162.800 225.750 163.500 ;
        RECT 20.200 149.800 20.750 150.500 ;
        RECT 25.200 149.800 25.750 150.500 ;
        RECT 30.200 149.800 44.350 150.500 ;
        RECT 49.200 149.800 49.750 150.500 ;
        RECT 54.200 149.800 81.950 150.500 ;
        RECT 87.200 149.800 114.950 150.500 ;
        RECT 180.200 149.800 180.750 150.500 ;
        RECT 185.200 149.800 185.750 150.500 ;
        RECT 190.200 149.800 197.550 150.500 ;
        RECT 203.200 149.800 203.750 150.500 ;
        RECT 208.200 149.800 232.550 150.500 ;
        RECT 238.200 149.800 262.550 150.500 ;
        RECT 20.000 119.300 20.550 120.000 ;
        RECT 25.000 119.300 31.950 120.000 ;
        RECT 37.000 119.300 43.950 120.000 ;
        RECT 49.000 119.300 52.750 120.000 ;
        RECT 58.000 119.300 61.750 120.000 ;
        RECT 67.000 119.300 93.150 120.000 ;
        RECT 98.000 119.300 124.150 120.000 ;
        RECT 129.000 119.300 132.750 120.000 ;
        RECT 138.000 119.300 141.750 120.000 ;
        RECT 147.000 119.300 150.750 120.000 ;
        RECT 180.000 119.300 180.550 120.000 ;
        RECT 185.000 119.300 188.750 120.000 ;
        RECT 194.000 119.300 197.750 120.000 ;
        RECT 203.000 119.300 203.550 120.000 ;
        RECT 208.000 119.300 208.550 120.000 ;
        RECT 213.000 119.300 235.950 120.000 ;
        RECT 241.000 119.300 263.950 120.000 ;
        RECT 269.000 119.300 272.750 120.000 ;
        RECT 278.000 119.300 281.750 120.000 ;
        RECT 287.000 119.300 290.750 120.000 ;
        RECT 199.350 39.800 199.900 40.500 ;
        RECT 204.350 39.800 204.900 40.500 ;
        RECT 209.350 39.800 209.900 40.500 ;
        RECT 214.350 39.800 214.900 40.500 ;
        RECT 249.350 39.800 249.900 40.500 ;
        RECT 254.350 39.800 254.900 40.500 ;
        RECT 259.350 39.800 259.900 40.500 ;
        RECT 264.350 39.800 264.900 40.500 ;
        RECT 199.350 24.300 202.450 25.000 ;
        RECT 207.350 24.300 210.450 25.000 ;
        RECT 215.350 24.300 218.450 25.000 ;
        RECT 249.350 24.300 252.450 25.000 ;
        RECT 257.350 24.300 260.450 25.000 ;
        RECT 265.350 24.300 268.450 25.000 ;
      LAYER met3 ;
        RECT 50.500 60.200 92.500 102.200 ;
        RECT 96.500 60.200 122.700 101.400 ;
        RECT 126.500 60.200 152.700 101.400 ;
        RECT 50.500 15.200 92.500 57.200 ;
        RECT 96.500 15.200 122.700 56.400 ;
        RECT 126.500 15.200 152.700 56.400 ;
        RECT 156.500 50.200 177.700 81.400 ;
        RECT 156.500 15.200 177.700 46.400 ;
      LAYER met4 ;
        RECT 51.300 61.000 91.700 101.400 ;
        RECT 97.300 61.000 121.900 100.600 ;
        RECT 127.300 61.000 151.900 100.600 ;
        RECT 51.300 16.000 91.700 56.400 ;
        RECT 97.300 16.000 121.900 55.600 ;
        RECT 127.300 16.000 151.900 55.600 ;
        RECT 157.300 51.000 176.900 80.600 ;
        RECT 157.300 16.000 176.900 45.600 ;
  END
END tt_um_ctsd_modulator
END LIBRARY

